VERSION 5.7 ;
  NOWIREEXTENSIONATPIN ON ;
  DIVIDERCHAR "/" ;
  BUSBITCHARS "[]" ;
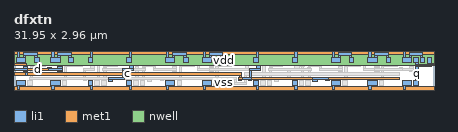
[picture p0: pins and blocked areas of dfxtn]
MACRO dfxtn
  CLASS BLOCK ;
  FOREIGN dfxtn ;
  ORIGIN 6.780 0.340 ;
  SIZE 31.950 BY 2.960 ;
  PIN d
    ANTENNAGATEAREA 0.252000 ;
    PORT
      LAYER li1 ;
        RECT -3.460 1.330 -3.120 1.410 ;
        RECT -4.170 1.150 -3.120 1.330 ;
        RECT -3.460 1.070 -3.120 1.150 ;
      LAYER met1 ;
        RECT -6.780 1.510 -5.810 1.690 ;
        RECT -5.990 1.330 -5.810 1.510 ;
        RECT -4.200 1.330 -3.960 1.360 ;
        RECT -5.990 1.150 -3.930 1.330 ;
        RECT -4.200 1.120 -3.960 1.150 ;
    END
  END d
  PIN q
    ANTENNADIFFAREA 0.453600 ;
    PORT
      LAYER li1 ;
        RECT 23.620 1.750 23.960 2.150 ;
        RECT 23.780 1.580 23.960 1.750 ;
        RECT 24.640 1.690 24.980 2.150 ;
        RECT 24.640 1.580 25.170 1.690 ;
        RECT 23.780 1.510 25.170 1.580 ;
        RECT 23.780 1.410 24.980 1.510 ;
        RECT 23.780 0.370 23.960 1.410 ;
        RECT 23.620 -0.030 23.960 0.370 ;
    END
  END q
  PIN c
    ANTENNAGATEAREA 0.756000 ;
    PORT
      LAYER li1 ;
        RECT -6.070 1.330 -5.730 1.410 ;
        RECT 1.970 1.330 2.310 1.490 ;
        RECT 11.630 1.330 11.970 1.490 ;
        RECT -6.780 1.150 -5.730 1.330 ;
        RECT -6.070 1.070 -5.730 1.150 ;
        RECT -5.910 0.790 -5.730 1.070 ;
        RECT 1.440 1.150 2.310 1.330 ;
        RECT 11.100 1.150 11.970 1.330 ;
        RECT 1.440 0.610 1.620 1.150 ;
        RECT 11.100 0.610 11.280 1.150 ;
        RECT 0.400 0.430 1.620 0.610 ;
        RECT 10.340 0.430 11.280 0.610 ;
        RECT 15.940 0.430 17.160 0.610 ;
        RECT 0.400 0.270 0.740 0.430 ;
        RECT 15.940 0.270 16.280 0.430 ;
      LAYER met1 ;
        RECT -5.940 0.970 -5.700 1.000 ;
        RECT 1.410 0.970 1.650 1.000 ;
        RECT -6.780 0.790 10.520 0.970 ;
        RECT -5.940 0.760 -5.700 0.790 ;
        RECT 1.410 0.760 1.650 0.790 ;
        RECT 10.340 0.640 10.520 0.790 ;
        RECT 10.310 0.610 10.550 0.640 ;
        RECT 11.070 0.610 11.310 0.640 ;
        RECT 16.950 0.610 17.190 0.640 ;
        RECT 10.280 0.430 10.580 0.610 ;
        RECT 11.040 0.430 22.560 0.610 ;
        RECT 10.310 0.400 10.550 0.430 ;
        RECT 11.070 0.400 11.310 0.430 ;
        RECT 16.950 0.400 17.190 0.430 ;
    END
  END c
  PIN vdd
    ANTENNADIFFAREA 4.032000 ;
    PORT
      LAYER nwell ;
        RECT -6.780 1.560 25.170 2.400 ;
      LAYER li1 ;
        RECT -6.510 2.150 -6.330 2.590 ;
        RECT -6.070 2.320 -5.030 2.490 ;
        RECT -6.070 2.150 -5.890 2.320 ;
        RECT -6.590 1.750 -5.890 2.150 ;
        RECT -5.210 2.150 -5.030 2.320 ;
        RECT -3.900 2.150 -3.720 2.590 ;
        RECT -3.460 2.320 -2.420 2.490 ;
        RECT -3.460 2.150 -3.280 2.320 ;
        RECT -5.210 1.750 -4.870 2.150 ;
        RECT -3.980 1.750 -3.280 2.150 ;
        RECT -2.600 2.150 -2.420 2.320 ;
        RECT -0.970 2.150 -0.790 2.590 ;
        RECT 1.970 2.150 2.150 2.590 ;
        RECT 4.830 2.150 5.010 2.590 ;
        RECT 5.270 2.320 6.310 2.490 ;
        RECT 5.270 2.150 5.450 2.320 ;
        RECT -2.600 1.750 -2.260 2.150 ;
        RECT -1.130 1.750 -0.790 2.150 ;
        RECT 1.810 1.750 2.150 2.150 ;
        RECT 4.750 1.750 5.450 2.150 ;
        RECT 6.130 2.150 6.310 2.320 ;
        RECT 7.620 2.150 7.800 2.590 ;
        RECT 8.060 2.320 9.100 2.490 ;
        RECT 8.060 2.150 8.240 2.320 ;
        RECT 6.130 1.750 6.470 2.150 ;
        RECT 7.540 1.750 8.240 2.150 ;
        RECT 8.920 2.150 9.100 2.320 ;
        RECT 11.630 2.150 11.810 2.590 ;
        RECT 14.570 2.150 14.750 2.590 ;
        RECT 17.430 2.150 17.610 2.590 ;
        RECT 17.870 2.320 18.910 2.490 ;
        RECT 17.870 2.150 18.050 2.320 ;
        RECT 8.920 1.750 9.260 2.150 ;
        RECT 11.470 1.750 11.810 2.150 ;
        RECT 14.410 1.750 14.750 2.150 ;
        RECT 17.350 1.750 18.050 2.150 ;
        RECT 18.730 2.150 18.910 2.320 ;
        RECT 20.220 2.150 20.400 2.590 ;
        RECT 20.660 2.320 21.700 2.490 ;
        RECT 20.660 2.150 20.840 2.320 ;
        RECT 18.730 1.750 19.070 2.150 ;
        RECT 20.140 1.750 20.840 2.150 ;
        RECT 21.520 2.150 21.700 2.320 ;
        RECT 22.830 2.150 23.010 2.590 ;
        RECT 23.270 2.320 24.310 2.490 ;
        RECT 23.270 2.150 23.450 2.320 ;
        RECT 21.520 1.750 21.860 2.150 ;
        RECT 22.750 1.750 23.450 2.150 ;
        RECT 24.130 2.150 24.310 2.320 ;
        RECT 24.130 1.750 24.470 2.150 ;
      LAYER met1 ;
        RECT -6.780 2.380 25.170 2.620 ;
    END
  END vdd
  PIN vss
    ANTENNADIFFAREA 2.973600 ;
    PORT
      LAYER li1 ;
        RECT -6.590 -0.030 -5.890 0.370 ;
        RECT -3.980 -0.030 -3.280 0.370 ;
        RECT -1.130 -0.030 -0.790 0.370 ;
        RECT 1.810 -0.030 2.150 0.370 ;
        RECT 4.750 -0.030 5.450 0.370 ;
        RECT 7.540 -0.030 8.240 0.370 ;
        RECT 11.470 -0.030 11.810 0.370 ;
        RECT 14.410 -0.030 14.750 0.370 ;
        RECT 17.350 -0.030 18.050 0.370 ;
        RECT 20.140 -0.030 20.840 0.370 ;
        RECT 22.750 -0.030 23.450 0.370 ;
        RECT -6.510 -0.310 -6.330 -0.030 ;
        RECT -3.900 -0.310 -3.720 -0.030 ;
        RECT -0.970 -0.310 -0.790 -0.030 ;
        RECT 1.970 -0.310 2.150 -0.030 ;
        RECT 4.830 -0.310 5.010 -0.030 ;
        RECT 7.620 -0.310 7.800 -0.030 ;
        RECT 11.630 -0.310 11.810 -0.030 ;
        RECT 14.570 -0.310 14.750 -0.030 ;
        RECT 17.430 -0.310 17.610 -0.030 ;
        RECT 20.220 -0.310 20.400 -0.030 ;
        RECT 22.830 -0.310 23.010 -0.030 ;
      LAYER met1 ;
        RECT -6.780 -0.340 25.170 -0.100 ;
    END
  END vss
  OBS
      LAYER li1 ;
        RECT -0.460 2.320 0.580 2.490 ;
        RECT -0.460 2.150 -0.280 2.320 ;
        RECT 0.400 2.150 0.580 2.320 ;
        RECT 2.480 2.320 3.520 2.490 ;
        RECT 2.480 2.150 2.660 2.320 ;
        RECT 3.340 2.150 3.520 2.320 ;
        RECT 12.140 2.320 13.180 2.490 ;
        RECT 12.140 2.150 12.320 2.320 ;
        RECT 13.000 2.150 13.180 2.320 ;
        RECT 15.080 2.320 16.120 2.490 ;
        RECT 15.080 2.150 15.260 2.320 ;
        RECT 15.940 2.150 16.120 2.320 ;
        RECT -5.720 1.750 -5.380 2.150 ;
        RECT -5.560 1.580 -5.380 1.750 ;
        RECT -4.700 1.690 -4.360 2.150 ;
        RECT -3.110 1.750 -2.770 2.150 ;
        RECT -4.700 1.580 -4.170 1.690 ;
        RECT -5.560 1.510 -4.170 1.580 ;
        RECT -2.950 1.580 -2.770 1.750 ;
        RECT -2.090 1.690 -1.750 2.150 ;
        RECT -0.620 1.750 -0.280 2.150 ;
        RECT -0.110 1.750 0.230 2.150 ;
        RECT 0.400 1.750 0.740 2.150 ;
        RECT -2.090 1.580 -1.560 1.690 ;
        RECT -2.950 1.510 -1.560 1.580 ;
        RECT -5.560 1.410 -4.360 1.510 ;
        RECT -2.950 1.410 -1.750 1.510 ;
        RECT -5.560 0.370 -5.380 1.410 ;
        RECT -2.950 0.370 -2.770 1.410 ;
        RECT -0.970 1.330 -0.630 1.490 ;
        RECT -1.500 1.150 -0.630 1.330 ;
        RECT -1.500 0.430 -1.320 1.150 ;
        RECT -0.460 0.370 -0.280 1.750 ;
        RECT 0.050 1.580 0.230 1.750 ;
        RECT 0.910 1.745 1.250 2.150 ;
        RECT 2.320 1.750 2.660 2.150 ;
        RECT 2.830 1.750 3.170 2.150 ;
        RECT 3.340 1.750 3.680 2.150 ;
        RECT 0.910 1.580 1.080 1.745 ;
        RECT 0.050 1.410 1.080 1.580 ;
        RECT 0.050 0.370 0.230 1.410 ;
        RECT 2.480 0.370 2.660 1.750 ;
        RECT 2.990 1.580 3.170 1.750 ;
        RECT 3.850 1.745 4.190 2.150 ;
        RECT 5.620 1.750 5.960 2.150 ;
        RECT 3.850 1.580 4.020 1.745 ;
        RECT 2.990 1.410 4.020 1.580 ;
        RECT 5.780 1.580 5.960 1.750 ;
        RECT 6.640 1.690 6.980 2.150 ;
        RECT 8.410 1.750 8.750 2.150 ;
        RECT 6.640 1.580 7.350 1.690 ;
        RECT 5.780 1.510 7.350 1.580 ;
        RECT 5.780 1.410 6.980 1.510 ;
        RECT 2.990 0.370 3.170 1.410 ;
        RECT 3.850 1.330 4.020 1.410 ;
        RECT 5.270 1.330 5.610 1.410 ;
        RECT 3.850 1.150 5.610 1.330 ;
        RECT 5.270 1.070 5.610 1.150 ;
        RECT -5.720 -0.030 -5.380 0.370 ;
        RECT -3.110 -0.030 -2.770 0.370 ;
        RECT -0.620 -0.030 -0.280 0.370 ;
        RECT -0.110 -0.030 0.230 0.370 ;
        RECT 2.320 -0.030 2.660 0.370 ;
        RECT 2.830 -0.030 3.170 0.370 ;
        RECT 3.340 0.430 4.560 0.610 ;
        RECT 3.340 0.270 3.680 0.430 ;
        RECT 5.780 0.370 5.960 1.410 ;
        RECT 7.170 1.330 7.350 1.510 ;
        RECT 8.570 1.580 8.750 1.750 ;
        RECT 9.430 1.690 9.770 2.150 ;
        RECT 11.980 1.750 12.320 2.150 ;
        RECT 12.490 1.750 12.830 2.150 ;
        RECT 13.000 1.750 13.340 2.150 ;
        RECT 9.430 1.580 9.960 1.690 ;
        RECT 8.570 1.510 9.960 1.580 ;
        RECT 8.570 1.410 9.770 1.510 ;
        RECT 8.060 1.330 8.400 1.410 ;
        RECT 7.170 1.150 8.400 1.330 ;
        RECT 8.060 1.070 8.400 1.150 ;
        RECT 8.570 0.370 8.750 1.410 ;
        RECT 12.140 0.370 12.320 1.750 ;
        RECT 12.650 1.580 12.830 1.750 ;
        RECT 13.510 1.745 13.850 2.150 ;
        RECT 14.920 1.750 15.260 2.150 ;
        RECT 15.430 1.750 15.770 2.150 ;
        RECT 15.940 1.750 16.280 2.150 ;
        RECT 13.510 1.580 13.680 1.745 ;
        RECT 12.650 1.410 13.680 1.580 ;
        RECT 12.650 0.370 12.830 1.410 ;
        RECT 14.570 1.330 14.910 1.490 ;
        RECT 14.040 1.150 14.910 1.330 ;
        RECT 14.040 0.610 14.220 1.150 ;
        RECT 5.620 -0.030 5.960 0.370 ;
        RECT 8.410 -0.030 8.750 0.370 ;
        RECT 11.980 -0.030 12.320 0.370 ;
        RECT 12.490 -0.030 12.830 0.370 ;
        RECT 13.000 0.430 14.220 0.610 ;
        RECT 13.000 0.270 13.340 0.430 ;
        RECT 15.080 0.370 15.260 1.750 ;
        RECT 15.590 1.580 15.770 1.750 ;
        RECT 16.450 1.745 16.790 2.150 ;
        RECT 18.220 1.750 18.560 2.150 ;
        RECT 16.450 1.580 16.620 1.745 ;
        RECT 15.590 1.410 16.620 1.580 ;
        RECT 18.380 1.580 18.560 1.750 ;
        RECT 19.240 1.690 19.580 2.150 ;
        RECT 21.010 1.750 21.350 2.150 ;
        RECT 19.240 1.580 19.950 1.690 ;
        RECT 18.380 1.510 19.950 1.580 ;
        RECT 18.380 1.410 19.580 1.510 ;
        RECT 15.590 0.370 15.770 1.410 ;
        RECT 16.450 1.330 16.620 1.410 ;
        RECT 17.870 1.330 18.210 1.410 ;
        RECT 16.450 1.150 18.210 1.330 ;
        RECT 17.870 1.070 18.210 1.150 ;
        RECT 18.380 0.370 18.560 1.410 ;
        RECT 19.770 1.330 19.950 1.510 ;
        RECT 21.170 1.580 21.350 1.750 ;
        RECT 22.030 1.690 22.370 2.150 ;
        RECT 22.030 1.580 22.560 1.690 ;
        RECT 21.170 1.510 22.560 1.580 ;
        RECT 21.170 1.410 22.370 1.510 ;
        RECT 20.660 1.330 21.000 1.410 ;
        RECT 19.770 1.150 21.000 1.330 ;
        RECT 20.660 1.070 21.000 1.150 ;
        RECT 21.170 0.370 21.350 1.410 ;
        RECT 23.270 1.330 23.610 1.410 ;
        RECT 22.560 1.150 23.610 1.330 ;
        RECT 23.270 1.070 23.610 1.150 ;
        RECT 14.920 -0.030 15.260 0.370 ;
        RECT 15.430 -0.030 15.770 0.370 ;
        RECT 18.220 -0.030 18.560 0.370 ;
        RECT 21.010 -0.030 21.350 0.370 ;
      LAYER met1 ;
        RECT -0.540 2.070 -0.360 2.100 ;
        RECT 12.060 2.070 12.240 2.100 ;
        RECT -0.570 1.830 -0.330 2.070 ;
        RECT 12.030 1.830 12.270 2.070 ;
        RECT -1.800 1.690 -1.560 1.720 ;
        RECT -0.540 1.690 -0.360 1.830 ;
        RECT 2.450 1.690 2.690 1.720 ;
        RECT 8.540 1.690 8.780 1.720 ;
        RECT 12.060 1.690 12.240 1.830 ;
        RECT 15.050 1.690 15.290 1.720 ;
        RECT 21.140 1.690 21.380 1.720 ;
        RECT -1.830 1.510 -0.360 1.690 ;
        RECT 2.420 1.510 8.810 1.690 ;
        RECT 10.860 1.510 12.240 1.690 ;
        RECT 15.020 1.510 21.410 1.690 ;
        RECT -1.800 1.480 -1.560 1.510 ;
        RECT 2.450 1.480 2.690 1.510 ;
        RECT 8.540 1.480 8.780 1.510 ;
        RECT 0.020 1.330 0.260 1.360 ;
        RECT 2.960 1.330 3.200 1.360 ;
        RECT 8.110 1.330 8.350 1.360 ;
        RECT 10.860 1.330 11.040 1.510 ;
        RECT 15.050 1.480 15.290 1.510 ;
        RECT 21.140 1.480 21.380 1.510 ;
        RECT 12.620 1.330 12.860 1.360 ;
        RECT 15.560 1.330 15.800 1.360 ;
        RECT 20.710 1.330 20.950 1.360 ;
        RECT 22.530 1.330 22.770 1.360 ;
        RECT -0.010 1.150 3.230 1.330 ;
        RECT 8.080 1.150 11.040 1.330 ;
        RECT 12.590 1.150 15.830 1.330 ;
        RECT 20.680 1.150 22.800 1.330 ;
        RECT 0.020 1.120 0.260 1.150 ;
        RECT 2.960 1.120 3.200 1.150 ;
        RECT 8.110 1.120 8.350 1.150 ;
        RECT 12.620 1.120 12.860 1.150 ;
        RECT 15.560 1.120 15.800 1.150 ;
        RECT 20.710 1.120 20.950 1.150 ;
        RECT 22.530 1.120 22.770 1.150 ;
        RECT 14.010 0.970 14.250 1.000 ;
        RECT 10.720 0.790 22.560 0.970 ;
        RECT -5.590 0.610 -5.350 0.640 ;
        RECT -1.530 0.610 -1.290 0.640 ;
        RECT 4.350 0.610 4.590 0.640 ;
        RECT -5.620 0.430 10.140 0.610 ;
        RECT -5.590 0.400 -5.350 0.430 ;
        RECT -1.530 0.400 -1.290 0.430 ;
        RECT 4.350 0.400 4.590 0.430 ;
        RECT 9.960 0.260 10.140 0.430 ;
        RECT 10.720 0.260 10.900 0.790 ;
        RECT 14.010 0.760 14.250 0.790 ;
        RECT 9.960 0.080 10.900 0.260 ;
  END
END dfxtn
END LIBRARY

